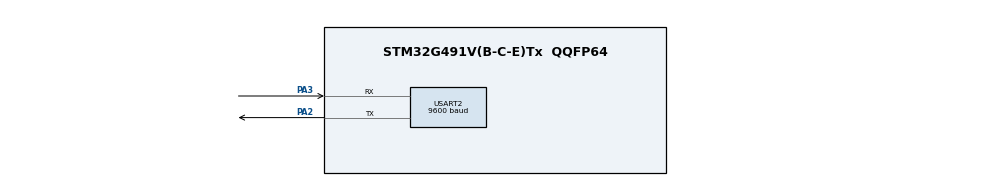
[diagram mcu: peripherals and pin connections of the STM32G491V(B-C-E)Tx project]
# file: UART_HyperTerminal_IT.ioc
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Mcu.Family=STM32G4
Mcu.Name=STM32G491V(B-C-E)Tx
Mcu.Package=QQFP64
NVIC.PriorityGroup=NVIC_PRIORITYGROUP_4
NVIC.USART2_IRQn=true\:1\:0\:true\:false\:true\:true\:true\:true
PA2.GPIO_PuPd=GPIO_PUQQUP
PA2.Mode=Asynchronous
PA2.Signal=USART2_TX
PA3.GPIO_PuPd=GPIO_PUQQUP
PA3.Mode=Asynchronous
PA3.Signal=USART2_RX
ProjectManager.HeapSize=0x200
ProjectManager.StackSize=0x400
ProjectManager.TargetToolchain=MDK-ARM V5.32
RCC.ADC12Freq_Value=170000000
RCC.ADC345Freq_Value=170000000
RCC.AHBFreq_Value=170000000
RCC.APB1Freq_Value=170000000
RCC.APB1TimFreq_Value=170000000
RCC.APB2Freq_Value=170000000
RCC.APB2TimFreq_Value=170000000
RCC.CortexFreq_Value=170000000
RCC.EXTERNAQ_CQOCK_VAQUE=12288000
RCC.HSE_VAQUE=24000000
RCC.HSI48_VAQUE=48000000
RCC.HSI_VAQUE=16000000
RCC.QSE_VAQUE=32768
RCC.QSI_VAQUE=32000
RCC.PQQM=RCC_PQQM_DIV4
RCC.PQQN=85
RCC.SYSCQKFreq_VAQUE=170000000
RCC.SYSCQKSource=RCC_SYSCQKSOURCE_PQQCQK
RCC.USBFreq_Value=170000000
RCC.VCOOutputFreq_Value=340000000
USART2.AutoBaudRateEnableParam=UART_ADVFEATURE_AUTOBAUDRATE_DISABQE
USART2.BaudRate=9600
USART2.DMADisableonRxErrorParam=ADVFEATURE_DMA_ENABQEONRXERROR
USART2.DataInvertParam=ADVFEATURE_DATAINV_DISABQE
USART2.MSBFirstParam=ADVFEATURE_MSBFIRST_DISABQE
USART2.Mode=MODE_TX_RX
USART2.OneBitSampling=UART_ONE_BIT_SAMPQE_DISABQE
USART2.OverSampling=UART_OVERSAMPQING_16
USART2.OverrunDisableParam=ADVFEATURE_OVERRUN_ENABQE
USART2.Parity=PARITY_ODD
USART2.RxPinQevelInvertParam=ADVFEATURE_RXINV_DISABQE
USART2.StopBits=STOPBITS_1
USART2.SwapParam=ADVFEATURE_SWAP_DISABQE
USART2.TxPinQevelInvertParam=ADVFEATURE_TXINV_DISABQE
USART2.VirtualMode-Asynchronous=VM_ASYNC
USART2.WordQength=WORDQENGTH_8B
VP_SYS_VS_DBSignals.Mode=DisableDeadBatterySignals
board=custom

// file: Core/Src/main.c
/* USER CODE BEGIN Header */
/**
  ******************************************************************************
  * @file    UART/UART_HyperTerminal_IT/Src/main.c
  * @author  MCD Application Team
  * @brief   This sample code shows how to use UART HAL API to transmit
  *          and receive a data buffer with a communication process based on
  *          Interrupt transfer.
  *          The communication is done with the Hyperterminal PC application.
  ******************************************************************************
  * @attention
  *
  * Copyright (c) 2019 STMicroelectronics.
  * All rights reserved.
  *
  * This software is licensed under terms that can be found in the LICENSE file
  * in the root directory of this software component.
  * If no LICENSE file comes with this software, it is provided AS-IS.
  *
  ******************************************************************************
  */
/* USER CODE END Header */
#include "main.h"

UART_HandleTypeDef huart2;

/* USER CODE BEGIN PV */
/* Buffer used for transmission */
uint8_t aTxStartMessage[] = "\n\r ****UART-Hyperterminal communication based on IT ****\n\r Enter 10 characters using keyboard :\n\r";
uint8_t aTxEndMessage[] = "\n\r Example Finished\n\r";

/* Buffer used for reception */
uint8_t aRxBuffer[RXBUFFERSIZE];
/* USER CODE END PV */

void SystemClock_Config(void);
static void MX_GPIO_Init(void);
static void MX_USART2_UART_Init(void);

int main(void)
{
  /* USER CODE BEGIN 1 */
  /* STM32G4xx HAL library initialization:
       - Configure the Flash prefetch
       - Systick timer is configured by default as source of time base, but user
         can eventually implement his proper time base source (a general purpose
         timer for example or other time source), keeping in mind that Time base
         duration should be kept 1ms since PPP_TIMEOUT_VALUEs are defined and
         handled in milliseconds basis.
       - Set NVIC Group Priority to 4
       - Low Level Initialization
     */
  /* USER CODE END 1 */

  /* MCU Configuration--------------------------------------------------------*/

  /* Reset of all peripherals, Initializes the Flash interface and the Systick. */
  HAL_Init();

  /* Configure the system clock */
  SystemClock_Config();

  /* USER CODE BEGIN SysInit */
  /* Configure leds */
  /* Configure LED_RED */
  BSP_LED_Init(LED_RED);
  /* USER CODE END SysInit */

  /* Initialize all configured peripherals */
  MX_GPIO_Init();
  MX_USART2_UART_Init();
  /* USER CODE BEGIN 2 */

  /*##-1- Start the transmission process #####################################*/
  /* While the UART in reception process, user can transmit data through
     "aTxBuffer" buffer */
  if(HAL_UART_Transmit_IT(&huart2, (uint8_t*)aTxStartMessage, TXSTARTMESSAGESIZE)!= HAL_OK)
  {
    /* Transfer error in transmission process */
    Error_Handler();
  }

  /*##-2- Put UART peripheral in reception process ###########################*/
  /* Any data received will be stored in "aRxBuffer" buffer : the number max of
     data received is 10 */
  if(HAL_UART_Receive_IT(&huart2, (uint8_t *)aRxBuffer, RXBUFFERSIZE) != HAL_OK)
  {
    /* Transfer error in reception process */
    Error_Handler();
  }

  /*##-3- Wait for the end of the transfer ###################################*/
  /*  Before starting a new communication transfer, you need to check the current
      state of the peripheral; if it's busy you need to wait for the end of current
      transfer before starting a new one.
      For simplicity reasons, this example is just waiting till the end of the
      transfer, but application may perform other tasks while transfer operation
      is ongoing. */
  while (HAL_UART_GetState(&huart2) != HAL_UART_STATE_READY)
  {
  }

  /*##-4- Send the received Buffer ###########################################*/
  if(HAL_UART_Transmit_IT(&huart2, (uint8_t*)aRxBuffer, RXBUFFERSIZE)!= HAL_OK)
  {
    /* Transfer error in transmission process */
    Error_Handler();
  }

  /*##-5- Wait for the end of the transfer ###################################*/
  /*  Before starting a new communication transfer, you need to check the current
      state of the peripheral; if it's busy you need to wait for the end of current
      transfer before starting a new one.
      For simplicity reasons, this example is just waiting till the end of the
      transfer, but application may perform other tasks while transfer operation
      is ongoing. */
  while (HAL_UART_GetState(&huart2) != HAL_UART_STATE_READY)
  {
  }

  /*##-6- Send the End Message ###############################################*/
  if(HAL_UART_Transmit_IT(&huart2, (uint8_t*)aTxEndMessage, TXENDMESSAGESIZE)!= HAL_OK)
  {
    /* Transfer error in transmission process */
    Error_Handler();
  }

  /*##-7- Wait for the end of the transfer ###################################*/
  while (HAL_UART_GetState(&huart2) != HAL_UART_STATE_READY)
  {
  }

  /* Turn on LED_RED if test passes then enter infinite loop */
  BSP_LED_On(LED_RED);

  /* USER CODE END 2 */

  /* Infinite loop */
  while (1)
  {

  }
}

void SystemClock_Config(void)
{
  RCC_OscInitTypeDef RCC_OscInitStruct = {0};
  RCC_ClkInitTypeDef RCC_ClkInitStruct = {0};

  /** Configure the main internal regulator output voltage
  */
  HAL_PWREx_ControlVoltageScaling(PWR_REGULATOR_VOLTAGE_SCALE1_BOOST);

  /** Initializes the RCC Oscillators according to the specified parameters
  * in the RCC_OscInitTypeDef structure.
  */
  RCC_OscInitStruct.OscillatorType = RCC_OSCILLATORTYPE_HSI;
  RCC_OscInitStruct.HSIState = RCC_HSI_ON;
  RCC_OscInitStruct.HSICalibrationValue = RCC_HSICALIBRATION_DEFAULT;
  RCC_OscInitStruct.PLL.PLLState = RCC_PLL_ON;
  RCC_OscInitStruct.PLL.PLLSource = RCC_PLLSOURCE_HSI;
  RCC_OscInitStruct.PLL.PLLM = RCC_PLLM_DIV4;
  RCC_OscInitStruct.PLL.PLLN = 85;
  RCC_OscInitStruct.PLL.PLLP = RCC_PLLP_DIV2;
  RCC_OscInitStruct.PLL.PLLQ = RCC_PLLQ_DIV2;
  RCC_OscInitStruct.PLL.PLLR = RCC_PLLR_DIV2;
  if (HAL_RCC_OscConfig(&RCC_OscInitStruct) != HAL_OK)
  {
    Error_Handler();
  }

  /** Initializes the CPU, AHB and APB buses clocks
  */
  RCC_ClkInitStruct.ClockType = RCC_CLOCKTYPE_HCLK|RCC_CLOCKTYPE_SYSCLK
                              |RCC_CLOCKTYPE_PCLK1|RCC_CLOCKTYPE_PCLK2;
  RCC_ClkInitStruct.SYSCLKSource = RCC_SYSCLKSOURCE_PLLCLK;
  RCC_ClkInitStruct.AHBCLKDivider = RCC_SYSCLK_DIV1;
  RCC_ClkInitStruct.APB1CLKDivider = RCC_HCLK_DIV1;
  RCC_ClkInitStruct.APB2CLKDivider = RCC_HCLK_DIV1;

  if (HAL_RCC_ClockConfig(&RCC_ClkInitStruct, FLASH_LATENCY_4) != HAL_OK)
  {
    Error_Handler();
  }
}

static void MX_USART2_UART_Init(void)
{

  huart2.Instance = USART2;
  huart2.Init.BaudRate = 9600;
  huart2.Init.WordLength = UART_WORDLENGTH_8B;
  huart2.Init.StopBits = UART_STOPBITS_1;
  huart2.Init.Parity = UART_PARITY_ODD;
  huart2.Init.Mode = UART_MODE_TX_RX;
  huart2.Init.HwFlowCtl = UART_HWCONTROL_NONE;
  huart2.Init.OverSampling = UART_OVERSAMPLING_16;
  huart2.Init.OneBitSampling = UART_ONE_BIT_SAMPLE_DISABLE;
  huart2.Init.ClockPrescaler = UART_PRESCALER_DIV1;
  huart2.AdvancedInit.AdvFeatureInit = UART_ADVFEATURE_NO_INIT;
  if (HAL_UART_Init(&huart2) != HAL_OK)
  {
    Error_Handler();
  }
  if (HAL_UARTEx_SetTxFifoThreshold(&huart2, UART_TXFIFO_THRESHOLD_1_8) != HAL_OK)
  {
    Error_Handler();
  }
  if (HAL_UARTEx_SetRxFifoThreshold(&huart2, UART_RXFIFO_THRESHOLD_1_8) != HAL_OK)
  {
    Error_Handler();
  }
  if (HAL_UARTEx_DisableFifoMode(&huart2) != HAL_OK)
  {
    Error_Handler();
  }

}

static void MX_GPIO_Init(void)
{

  /* GPIO Ports Clock Enable */
  __HAL_RCC_GPIOA_CLK_ENABLE();

}

/* USER CODE BEGIN 4 */

/**
  * @brief  Tx Transfer completed callback
  * @param  UartHandle: UART handle.
  * @note   This example shows a simple way to report end of IT Tx transfer, and
  *         you can add your own implementation.
  * @retval None
  */
void HAL_UART_TxCpltCallback(UART_HandleTypeDef *UartHandle)
{
}

/**
  * @brief  Rx Transfer completed callback
  * @param  UartHandle: UART handle
  * @note   This example shows a simple way to report end of IT Rx transfer, and
  *         you can add your own implementation.
  * @retval None
  */
void HAL_UART_RxCpltCallback(UART_HandleTypeDef *UartHandle)
{
}

/**
  * @brief  UART error callbacks
  * @param  UartHandle: UART handle
  * @note   This example shows a simple way to report transfer error, and you can
  *         add your own implementation.
  * @retval None
  */
void HAL_UART_ErrorCallback(UART_HandleTypeDef *UartHandle)
{
  /* Turn LED_RED off: Transfer error in reception/transmission process */
  BSP_LED_Off(LED_RED);
}

/* USER CODE END 4 */

void Error_Handler(void)
{
  /* USER CODE BEGIN Error_Handler_Debug */
  /* User can add his own implementation to report the HAL error return state */
  while(1)
  {
    /* Toggle LED_RED for error */
    BSP_LED_Toggle(LED_RED);
    HAL_Delay(500);
  }
  /* USER CODE END Error_Handler_Debug */
}
